VERSION 5.8 ;
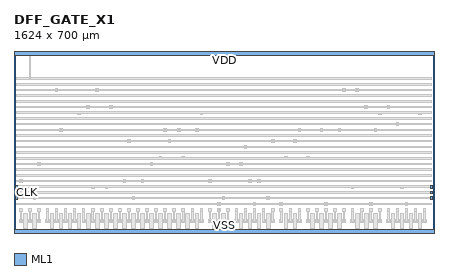
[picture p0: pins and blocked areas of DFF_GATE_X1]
MACRO DFF_GATE_X1
  CLASS CORE ;
  ORIGIN 0 0 ;
  SIZE 1624 BY 700 ;
  SITE ICPS2023_5_ROW700 ;
  PIN D
    DIRECTION INPUT ;
    USE SIGNAL ;
    PORT
      LAYER ML1 ;
        RECT 5 130 15 140 ;
        RECT 1609 130 1619 140 ;
    END
  END D
  PIN CLK
    DIRECTION INPUT ;
    USE SIGNAL ;
    PORT
      LAYER ML1 ;
        RECT 5 152 15 162 ;
        RECT 1609 152 1619 162 ;
    END
  END CLK
  PIN Q
    DIRECTION OUTPUT ;
    USE SIGNAL ;
    PORT
      LAYER ML1 ;
        RECT 5 174 15 184 ;
        RECT 1609 174 1619 184 ;
    END
  END Q
  PIN VDD
    DIRECTION INOUT ;
    USE POWER ;
    PORT
      LAYER ML1 ;
        RECT 0 688 1624 700 ;
    END
  END VDD
  PIN VSS
    DIRECTION INOUT ;
    USE GROUND ;
    PORT
      LAYER ML1 ;
        RECT 0 0 1624 12 ;
    END
  END VSS
  OBS
    LAYER ML1 ;
      RECT 20 39.5 33 52.5 ;
      RECT 55 39.5 68 52.5 ;
      RECT 90 39.5 103 52.5 ;
      RECT 37.5 16 50.5 29 ;
      RECT 37.5 63 50.5 76 ;
      RECT 37 16 51 76 ;
      RECT 72.5 16 85.5 29 ;
      RECT 72.5 63 85.5 76 ;
      RECT 72 16 86 76 ;
      RECT 23.5 46 29.5 89 ;
      RECT 21.5 84 31.5 94 ;
      RECT 21.5 196 31.5 206 ;
      RECT 58.5 46 64.5 89 ;
      RECT 56.5 84 66.5 94 ;
      RECT 56.5 592 66.5 602 ;
      RECT 93.5 46 99.5 89 ;
      RECT 91.5 84 101.5 94 ;
      RECT 91.5 262 101.5 272 ;
      RECT 39 152 49 162 ;
      RECT 74 130 84 140 ;
      RECT 123 39.5 136 52.5 ;
      RECT 158 39.5 171 52.5 ;
      RECT 193 39.5 206 52.5 ;
      RECT 228 39.5 241 52.5 ;
      RECT 263 39.5 276 52.5 ;
      RECT 298 39.5 311 52.5 ;
      RECT 333 39.5 346 52.5 ;
      RECT 368 39.5 381 52.5 ;
      RECT 403 39.5 416 52.5 ;
      RECT 438 39.5 451 52.5 ;
      RECT 473 39.5 486 52.5 ;
      RECT 508 39.5 521 52.5 ;
      RECT 543 39.5 556 52.5 ;
      RECT 578 39.5 591 52.5 ;
      RECT 613 39.5 626 52.5 ;
      RECT 648 39.5 661 52.5 ;
      RECT 683 39.5 696 52.5 ;
      RECT 718 39.5 731 52.5 ;
      RECT 140.5 16 153.5 29 ;
      RECT 140.5 63 153.5 76 ;
      RECT 140 16 154 76 ;
      RECT 175.5 16 188.5 29 ;
      RECT 175.5 63 188.5 76 ;
      RECT 175 16 189 76 ;
      RECT 210.5 16 223.5 29 ;
      RECT 210.5 63 223.5 76 ;
      RECT 210 16 224 76 ;
      RECT 245.5 16 258.5 29 ;
      RECT 245.5 63 258.5 76 ;
      RECT 245 16 259 76 ;
      RECT 280.5 16 293.5 29 ;
      RECT 280.5 63 293.5 76 ;
      RECT 280 16 294 76 ;
      RECT 315.5 16 328.5 29 ;
      RECT 315.5 63 328.5 76 ;
      RECT 315 16 329 76 ;
      RECT 350.5 16 363.5 29 ;
      RECT 350.5 63 363.5 76 ;
      RECT 350 16 364 76 ;
      RECT 385.5 16 398.5 29 ;
      RECT 385.5 63 398.5 76 ;
      RECT 385 16 399 76 ;
      RECT 420.5 16 433.5 29 ;
      RECT 420.5 63 433.5 76 ;
      RECT 420 16 434 76 ;
      RECT 455.5 16 468.5 29 ;
      RECT 455.5 63 468.5 76 ;
      RECT 455 16 469 76 ;
      RECT 490.5 16 503.5 29 ;
      RECT 490.5 63 503.5 76 ;
      RECT 490 16 504 76 ;
      RECT 525.5 16 538.5 29 ;
      RECT 525.5 63 538.5 76 ;
      RECT 525 16 539 76 ;
      RECT 560.5 16 573.5 29 ;
      RECT 560.5 63 573.5 76 ;
      RECT 560 16 574 76 ;
      RECT 595.5 16 608.5 29 ;
      RECT 595.5 63 608.5 76 ;
      RECT 595 16 609 76 ;
      RECT 630.5 16 643.5 29 ;
      RECT 630.5 63 643.5 76 ;
      RECT 630 16 644 76 ;
      RECT 665.5 16 678.5 29 ;
      RECT 665.5 63 678.5 76 ;
      RECT 665 16 679 76 ;
      RECT 700.5 16 713.5 29 ;
      RECT 700.5 63 713.5 76 ;
      RECT 700 16 714 76 ;
      RECT 126.5 46 132.5 89 ;
      RECT 124.5 84 134.5 94 ;
      RECT 124.5 592 134.5 602 ;
      RECT 161.5 46 167.5 89 ;
      RECT 159.5 84 169.5 94 ;
      RECT 159.5 548 169.5 558 ;
      RECT 196.5 46 202.5 89 ;
      RECT 194.5 84 204.5 94 ;
      RECT 194.5 592 204.5 602 ;
      RECT 231.5 46 237.5 89 ;
      RECT 229.5 84 239.5 94 ;
      RECT 229.5 504 239.5 514 ;
      RECT 266.5 46 272.5 89 ;
      RECT 264.5 84 274.5 94 ;
      RECT 264.5 592 274.5 602 ;
      RECT 301.5 46 307.5 89 ;
      RECT 299.5 84 309.5 94 ;
      RECT 299.5 174 309.5 184 ;
      RECT 336.5 46 342.5 89 ;
      RECT 334.5 84 344.5 94 ;
      RECT 334.5 592 344.5 602 ;
      RECT 371.5 46 377.5 89 ;
      RECT 369.5 84 379.5 94 ;
      RECT 369.5 482 379.5 492 ;
      RECT 406.5 46 412.5 89 ;
      RECT 404.5 84 414.5 94 ;
      RECT 404.5 592 414.5 602 ;
      RECT 441.5 46 447.5 89 ;
      RECT 439.5 84 449.5 94 ;
      RECT 439.5 350 449.5 360 ;
      RECT 476.5 46 482.5 89 ;
      RECT 474.5 84 484.5 94 ;
      RECT 474.5 592 484.5 602 ;
      RECT 511.5 46 517.5 89 ;
      RECT 509.5 84 519.5 94 ;
      RECT 509.5 306 519.5 316 ;
      RECT 546.5 46 552.5 89 ;
      RECT 544.5 84 554.5 94 ;
      RECT 544.5 592 554.5 602 ;
      RECT 581.5 46 587.5 89 ;
      RECT 579.5 84 589.5 94 ;
      RECT 579.5 394 589.5 404 ;
      RECT 616.5 46 622.5 89 ;
      RECT 614.5 84 624.5 94 ;
      RECT 614.5 592 624.5 602 ;
      RECT 651.5 46 657.5 89 ;
      RECT 649.5 84 659.5 94 ;
      RECT 649.5 284 659.5 294 ;
      RECT 686.5 46 692.5 89 ;
      RECT 684.5 84 694.5 94 ;
      RECT 684.5 592 694.5 602 ;
      RECT 721.5 46 727.5 89 ;
      RECT 719.5 84 729.5 94 ;
      RECT 719.5 460 729.5 470 ;
      RECT 142 152 152 162 ;
      RECT 177 394 187 404 ;
      RECT 212 152 222 162 ;
      RECT 247 460 257 470 ;
      RECT 282 482 292 492 ;
      RECT 317 548 327 558 ;
      RECT 352 174 362 184 ;
      RECT 387 504 397 514 ;
      RECT 422 196 432 206 ;
      RECT 457 130 467 140 ;
      RECT 492 196 502 206 ;
      RECT 527 262 537 272 ;
      RECT 562 284 572 294 ;
      RECT 597 350 607 360 ;
      RECT 632 394 642 404 ;
      RECT 667 306 677 316 ;
      RECT 702 394 712 404 ;
      RECT 751 39.5 764 52.5 ;
      RECT 786 39.5 799 52.5 ;
      RECT 821 39.5 834 52.5 ;
      RECT 768.5 16 781.5 29 ;
      RECT 768.5 63 781.5 76 ;
      RECT 768 16 782 76 ;
      RECT 803.5 16 816.5 29 ;
      RECT 803.5 63 816.5 76 ;
      RECT 803 16 817 76 ;
      RECT 754.5 46 760.5 89 ;
      RECT 752.5 84 762.5 94 ;
      RECT 752.5 196 762.5 206 ;
      RECT 789.5 46 795.5 89 ;
      RECT 787.5 84 797.5 94 ;
      RECT 787.5 108 797.5 118 ;
      RECT 824.5 46 830.5 89 ;
      RECT 822.5 84 832.5 94 ;
      RECT 822.5 262 832.5 272 ;
      RECT 770 152 780 162 ;
      RECT 805 130 815 140 ;
      RECT 854 39.5 867 52.5 ;
      RECT 889 39.5 902 52.5 ;
      RECT 924 39.5 937 52.5 ;
      RECT 959 39.5 972 52.5 ;
      RECT 994 39.5 1007 52.5 ;
      RECT 871.5 16 884.5 29 ;
      RECT 871.5 63 884.5 76 ;
      RECT 871 16 885 76 ;
      RECT 906.5 16 919.5 29 ;
      RECT 906.5 63 919.5 76 ;
      RECT 906 16 920 76 ;
      RECT 941.5 16 954.5 29 ;
      RECT 941.5 63 954.5 76 ;
      RECT 941 16 955 76 ;
      RECT 976.5 16 989.5 29 ;
      RECT 976.5 63 989.5 76 ;
      RECT 976 16 990 76 ;
      RECT 857.5 46 863.5 89 ;
      RECT 855.5 84 865.5 94 ;
      RECT 855.5 306 865.5 316 ;
      RECT 892.5 46 898.5 89 ;
      RECT 890.5 84 900.5 94 ;
      RECT 890.5 328 900.5 338 ;
      RECT 927.5 46 933.5 89 ;
      RECT 925.5 84 935.5 94 ;
      RECT 925.5 108 935.5 118 ;
      RECT 962.5 46 968.5 89 ;
      RECT 960.5 84 970.5 94 ;
      RECT 960.5 372 970.5 382 ;
      RECT 997.5 46 1003.5 89 ;
      RECT 995.5 84 1005.5 94 ;
      RECT 995.5 350 1005.5 360 ;
      RECT 873 262 883 272 ;
      RECT 908 196 918 206 ;
      RECT 943 196 953 206 ;
      RECT 978 130 988 140 ;
      RECT 1027 39.5 1040 52.5 ;
      RECT 1062 39.5 1075 52.5 ;
      RECT 1097 39.5 1110 52.5 ;
      RECT 1044.5 16 1057.5 29 ;
      RECT 1044.5 63 1057.5 76 ;
      RECT 1044 16 1058 76 ;
      RECT 1079.5 16 1092.5 29 ;
      RECT 1079.5 63 1092.5 76 ;
      RECT 1079 16 1093 76 ;
      RECT 1030.5 46 1036.5 89 ;
      RECT 1028.5 84 1038.5 94 ;
      RECT 1028.5 108 1038.5 118 ;
      RECT 1065.5 46 1071.5 89 ;
      RECT 1063.5 84 1073.5 94 ;
      RECT 1063.5 240 1073.5 250 ;
      RECT 1100.5 46 1106.5 89 ;
      RECT 1098.5 84 1108.5 94 ;
      RECT 1098.5 394 1108.5 404 ;
      RECT 1046 284 1056 294 ;
      RECT 1081 350 1091 360 ;
      RECT 1130 39.5 1143 52.5 ;
      RECT 1165 39.5 1178 52.5 ;
      RECT 1200 39.5 1213 52.5 ;
      RECT 1235 39.5 1248 52.5 ;
      RECT 1270 39.5 1283 52.5 ;
      RECT 1147.5 16 1160.5 29 ;
      RECT 1147.5 63 1160.5 76 ;
      RECT 1147 16 1161 76 ;
      RECT 1182.5 16 1195.5 29 ;
      RECT 1182.5 63 1195.5 76 ;
      RECT 1182 16 1196 76 ;
      RECT 1217.5 16 1230.5 29 ;
      RECT 1217.5 63 1230.5 76 ;
      RECT 1217 16 1231 76 ;
      RECT 1252.5 16 1265.5 29 ;
      RECT 1252.5 63 1265.5 76 ;
      RECT 1252 16 1266 76 ;
      RECT 1133.5 46 1139.5 89 ;
      RECT 1131.5 84 1141.5 94 ;
      RECT 1131.5 284 1141.5 294 ;
      RECT 1168.5 46 1174.5 89 ;
      RECT 1166.5 84 1176.5 94 ;
      RECT 1166.5 218 1176.5 228 ;
      RECT 1203.5 46 1209.5 89 ;
      RECT 1201.5 84 1211.5 94 ;
      RECT 1201.5 108 1211.5 118 ;
      RECT 1238.5 46 1244.5 89 ;
      RECT 1236.5 84 1246.5 94 ;
      RECT 1236.5 570 1246.5 580 ;
      RECT 1273.5 46 1279.5 89 ;
      RECT 1271.5 84 1281.5 94 ;
      RECT 1271.5 548 1281.5 558 ;
      RECT 1149 306 1159 316 ;
      RECT 1184 394 1194 404 ;
      RECT 1219 152 1229 162 ;
      RECT 1254 394 1264 404 ;
      RECT 1303 39.5 1316 52.5 ;
      RECT 1338 39.5 1351 52.5 ;
      RECT 1373 39.5 1386 52.5 ;
      RECT 1408 39.5 1421 52.5 ;
      RECT 1320.5 16 1333.5 29 ;
      RECT 1320.5 63 1333.5 76 ;
      RECT 1320 16 1334 76 ;
      RECT 1355.5 16 1368.5 29 ;
      RECT 1355.5 63 1368.5 76 ;
      RECT 1355 16 1369 76 ;
      RECT 1390.5 16 1403.5 29 ;
      RECT 1390.5 63 1403.5 76 ;
      RECT 1390 16 1404 76 ;
      RECT 1306.5 46 1312.5 89 ;
      RECT 1304.5 84 1314.5 94 ;
      RECT 1304.5 174 1314.5 184 ;
      RECT 1341.5 46 1347.5 89 ;
      RECT 1339.5 84 1349.5 94 ;
      RECT 1339.5 438 1349.5 448 ;
      RECT 1376.5 46 1382.5 89 ;
      RECT 1374.5 84 1384.5 94 ;
      RECT 1374.5 108 1384.5 118 ;
      RECT 1411.5 46 1417.5 89 ;
      RECT 1409.5 84 1419.5 94 ;
      RECT 1409.5 460 1419.5 470 ;
      RECT 1322 548 1332 558 ;
      RECT 1357 482 1367 492 ;
      RECT 1392 394 1402 404 ;
      RECT 1441 39.5 1454 52.5 ;
      RECT 1476 39.5 1489 52.5 ;
      RECT 1511 39.5 1524 52.5 ;
      RECT 1546 39.5 1559 52.5 ;
      RECT 1581 39.5 1594 52.5 ;
      RECT 1458.5 16 1471.5 29 ;
      RECT 1458.5 63 1471.5 76 ;
      RECT 1458 16 1472 76 ;
      RECT 1493.5 16 1506.5 29 ;
      RECT 1493.5 63 1506.5 76 ;
      RECT 1493 16 1507 76 ;
      RECT 1528.5 16 1541.5 29 ;
      RECT 1528.5 63 1541.5 76 ;
      RECT 1528 16 1542 76 ;
      RECT 1563.5 16 1576.5 29 ;
      RECT 1563.5 63 1576.5 76 ;
      RECT 1563 16 1577 76 ;
      RECT 1444.5 46 1450.5 89 ;
      RECT 1442.5 84 1452.5 94 ;
      RECT 1442.5 482 1452.5 492 ;
      RECT 1479.5 46 1485.5 89 ;
      RECT 1477.5 84 1487.5 94 ;
      RECT 1477.5 416 1487.5 426 ;
      RECT 1514.5 46 1520.5 89 ;
      RECT 1512.5 84 1522.5 94 ;
      RECT 1512.5 108 1522.5 118 ;
      RECT 1549.5 46 1555.5 89 ;
      RECT 1547.5 84 1557.5 94 ;
      RECT 1547.5 526 1557.5 536 ;
      RECT 1584.5 46 1590.5 89 ;
      RECT 1582.5 84 1592.5 94 ;
      RECT 1582.5 504 1592.5 514 ;
      RECT 1460 504 1470 514 ;
      RECT 1495 174 1505 184 ;
      RECT 1530 152 1540 162 ;
      RECT 1565 460 1575 470 ;
      RECT 10 110 1614 116 ;
      RECT 10 132 1614 138 ;
      RECT 10 154 1614 160 ;
      RECT 10 176 1614 182 ;
      RECT 10 198 1614 204 ;
      RECT 10 220 1614 226 ;
      RECT 10 242 1614 248 ;
      RECT 10 264 1614 270 ;
      RECT 10 286 1614 292 ;
      RECT 10 308 1614 314 ;
      RECT 10 330 1614 336 ;
      RECT 10 352 1614 358 ;
      RECT 10 374 1614 380 ;
      RECT 10 396 1614 402 ;
      RECT 10 418 1614 424 ;
      RECT 10 440 1614 446 ;
      RECT 10 462 1614 468 ;
      RECT 10 484 1614 490 ;
      RECT 10 506 1614 512 ;
      RECT 10 528 1614 534 ;
      RECT 10 550 1614 556 ;
      RECT 10 572 1614 578 ;
      RECT 10 594 1614 600 ;
      RECT 789.5 3 795.5 92 ;
      RECT 58.5 594 64.5 697 ;
  END
END DFF_GATE_X1
